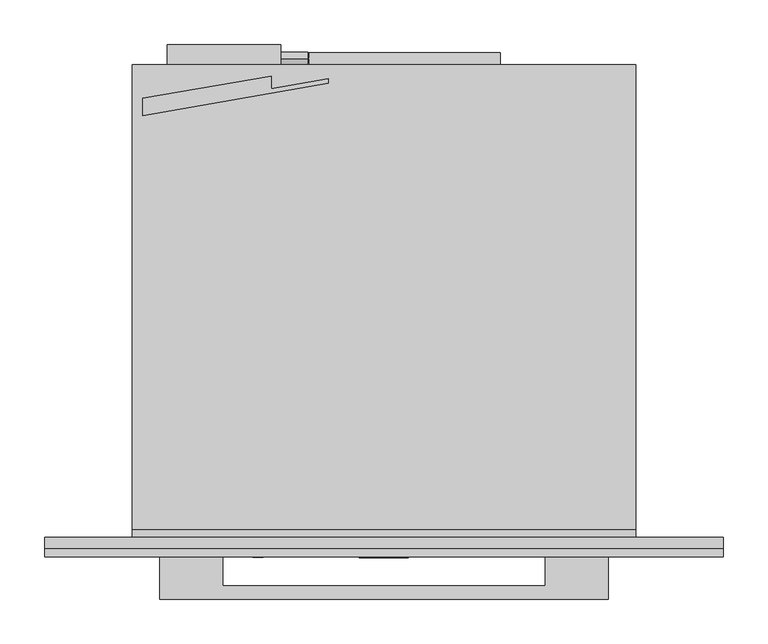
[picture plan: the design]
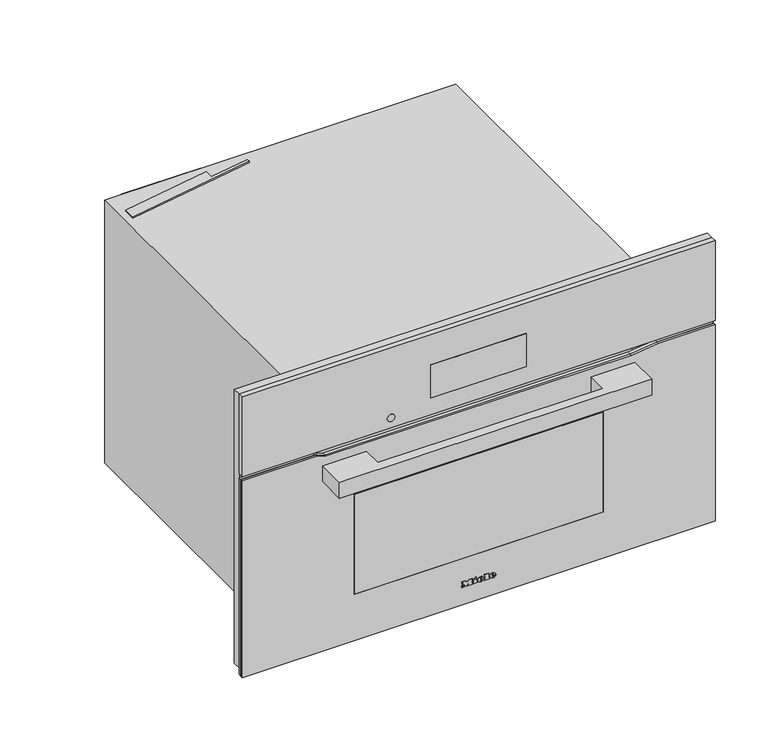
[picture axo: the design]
"""IFC4 building model written with IfcOpenShell, lengths in millimetres: proxy geometry."""

from ifc_helpers import new_model, si_unit, point, frame, frame_2d, origin, place, context, project, spatial, polyline, circle_curve, ellipse_curve, trimmed, segment, composite_curve, outline, extrude, faceted_brep, source, transform, mapped, element, save
from ifc_brep_helpers import plane_surface, cylinder_surface, revolved_surface, extruded_surface, advanced_brep


def specialty_equipment_e0231a5e(model_context):
    return source(origin(), model_context, "Body", "SolidModel", [
        advanced_brep(
        [(21.28, -23.0, 36.133), (21.28, -23.0, 37.042), (27.301, -23.0, 37.042), (16.825, -23.0, 37.042), (19.3, -23.0, 34.0), (27.148, -23.0, 36.133), (24.43, -23.0, 36.133), (22.288, -23.0, 35.125), (21.28, -23.0, 38.194), (21.28, -23.0, 39.175), (22.819, -23.0, 39.175), (22.819, -23.0, 38.194), (21.28, -22.0, 36.133), (22.288, -22.0, 35.125), (24.43, -22.0, 36.133), (27.148, -22.0, 36.133), (19.3, -22.0, 34.0), (16.825, -22.0, 37.042), (27.301, -22.0, 37.042), (21.28, -22.0, 37.042), (21.28, -22.0, 38.194), (22.819, -22.0, 38.194), (22.819, -22.0, 39.175), (21.28, -22.0, 39.175)],
        [
            (0, 1),
            (1, 2),
            (2, 3, ellipse_curve(frame((22.063, -23.0, 37.042), z_axis=(0.0, -1.0, 0.0), x_axis=(-1.0, 0.0, 0.0)), 5.238, 4.329)),
            (3, 4, circle_curve(frame((20.3080491, -23.0, 37.348), z_axis=(0.0, -1.0, 0.0), x_axis=(0.0, 0.0, -1.0)), 3.4964649)),
            (4, 5, circle_curve(frame((21.9581428, -23.0, 39.724), z_axis=(0.0, -1.0, 0.0), x_axis=(0.0, 0.0, -1.0)), 6.3110933)),
            (5, 6),
            (6, 7, circle_curve(frame((22.7279412, -23.0, 36.97), z_axis=(0.0, 1.0, 0.0), x_axis=(0.0, 0.0, -1.0)), 1.896727)),
            (7, 0, circle_curve(frame((22.288, -23.0, 36.133), z_axis=(0.0, 1.0, 0.0), x_axis=(0.0, 0.0, -1.0)), 1.008)),
            (8, 9),
            (9, 10, circle_curve(frame((22.0495, -23.0, 39.175), z_axis=(0.0, 1.0, 0.0), x_axis=(0.0, 0.0, -1.0)), 0.7695)),
            (10, 11),
            (11, 8),
            (12, 13, circle_curve(frame((22.288, -22.0, 36.133), z_axis=(0.0, -1.0, 0.0), x_axis=(0.0, 0.0, -1.0)), 1.008)),
            (13, 14, circle_curve(frame((22.7279412, -22.0, 36.97), z_axis=(0.0, -1.0, 0.0), x_axis=(0.0, 0.0, -1.0)), 1.896727)),
            (14, 15),
            (15, 16, circle_curve(frame((21.9581428, -22.0, 39.724), z_axis=(0.0, 1.0, 0.0), x_axis=(0.0, 0.0, -1.0)), 6.3110933)),
            (16, 17, circle_curve(frame((20.3080491, -22.0, 37.348), z_axis=(0.0, 1.0, 0.0), x_axis=(0.0, 0.0, -1.0)), 3.4964649)),
            (17, 18, ellipse_curve(frame((22.063, -22.0, 37.042), z_axis=(0.0, 1.0, 0.0), x_axis=(-1.0, 0.0, 0.0)), 5.238, 4.329)),
            (18, 19),
            (19, 12),
            (20, 21),
            (21, 22),
            (22, 23, circle_curve(frame((22.0495, -22.0, 39.175), z_axis=(0.0, -1.0, 0.0), x_axis=(0.0, 0.0, -1.0)), 0.7695)),
            (23, 20),
            (0, 12),
            (19, 1),
            (18, 2),
            (5, 15),
            (14, 6),
            (17, 3),
            (13, 7),
            (16, 4),
            (8, 20),
            (23, 9),
            (22, 10),
            (21, 11),
        ],
        [
            plane_surface(frame((21.28, -23.0, 37.042), z_axis=(0.0, -1.0, 0.0), x_axis=(0.0, 0.0, 1.0))),
            plane_surface(frame((21.28, -22.0, 37.042), z_axis=(0.0, 1.0, 0.0), x_axis=(0.0, 0.0, -1.0))),
            plane_surface(frame((21.28, -23.0, 36.133), z_axis=(1.0, 0.0, 0.0), x_axis=(0.0, 1.0, 0.0))),
            plane_surface(frame((21.28, -23.0, 37.042), z_axis=(0.0, 0.0, -1.0), x_axis=(0.0, 1.0, 0.0))),
            plane_surface(frame((27.148, -23.0, 36.133), z_axis=(0.0, 0.0, 1.0), x_axis=(0.0, 1.0, 0.0))),
            extruded_surface(trimmed(ellipse_curve(frame((22.063, -21.0, 37.042), z_axis=(0.0, -1.0, 0.0), x_axis=(-1.0, 0.0, 0.0)), 5.238, 4.329), [point((27.301, -21.0, 37.042))], [point((16.825, -21.0, 37.042))], True, "CARTESIAN"), (0.0, -1.0, 0.0), 1.0),
            revolved_surface(polyline([(22.7279412, -22.0, 35.073273), (22.7279412, -23.0, 35.073273)]), (22.7279412, -22.0, 36.97), (0.0, 1.0, 0.0)),
            revolved_surface(polyline([(22.288, -22.0, 35.125), (22.288, -23.0, 35.125)]), (22.288, -22.0, 36.133), (0.0, 1.0, 0.0)),
            cylinder_surface(frame((20.3080491, -22.0, 37.348), z_axis=(0.0, -1.0, 0.0), x_axis=(0.0, 0.0, -1.0)), 3.4964649),
            cylinder_surface(frame((21.9581428, -22.0, 39.724), z_axis=(0.0, -1.0, 0.0), x_axis=(0.0, 0.0, -1.0)), 6.3110933),
            plane_surface(frame((21.28, -23.0, 38.194), z_axis=(1.0, 0.0, 0.0), x_axis=(0.0, 1.0, 0.0))),
            revolved_surface(polyline([(22.0495, -22.0, 38.405499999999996), (22.0495, -23.0, 38.405499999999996)]), (22.0495, -22.0, 39.175), (0.0, 1.0, 0.0)),
            plane_surface(frame((22.819, -23.0, 39.175), z_axis=(-1.0, 0.0, 0.0), x_axis=(0.0, 1.0, 0.0))),
            plane_surface(frame((22.819, -23.0, 38.194), z_axis=(0.0, 0.0, 1.0), x_axis=(0.0, 1.0, 0.0))),
        ],
        [
            (0, [[1, 2, 3, 4, 5, 6, 7, 8], [9, 10, 11, 12]]),
            (1, [[13, 14, 15, 16, 17, 18, 19, 20], [21, 22, 23, 24]]),
            (2, [[-1, 25, -20, 26]]),
            (3, [[-2, -26, -19, 27]]),
            (4, [[-6, 28, -15, 29]]),
            (5, [[-3, -27, -18, 30]]),
            (6, [[-7, -29, -14, 31]]),
            (7, [[-8, -31, -13, -25]]),
            (8, [[-4, -30, -17, 32]]),
            (9, [[-5, -32, -16, -28]]),
            (10, [[-9, 33, -24, 34]]),
            (11, [[-10, -34, -23, 35]]),
            (12, [[-11, -35, -22, 36]]),
            (13, [[-12, -36, -21, -33]]),
        ],
    ),
        advanced_brep(
        [(2.497, -23.0, 36.133), (2.497, -23.0, 37.042), (8.518, -23.0, 37.042), (-1.958, -23.0, 37.042), (0.517, -23.0, 34.0), (8.365, -23.0, 36.133), (5.647, -23.0, 36.133), (3.505, -23.0, 35.125), (2.497, -23.0, 38.194), (2.497, -23.0, 39.175), (4.036, -23.0, 39.175), (4.036, -23.0, 38.194), (2.497, -22.0, 36.133), (3.505, -22.0, 35.125), (5.647, -22.0, 36.133), (8.365, -22.0, 36.133), (0.517, -22.0, 34.0), (-1.958, -22.0, 37.042), (8.518, -22.0, 37.042), (2.497, -22.0, 37.042), (2.497, -22.0, 38.194), (4.036, -22.0, 38.194), (4.036, -22.0, 39.175), (2.497, -22.0, 39.175)],
        [
            (0, 1),
            (1, 2),
            (2, 3, ellipse_curve(frame((3.28, -23.0, 37.042), z_axis=(0.0, -1.0, 0.0), x_axis=(-1.0, 0.0, 0.0)), 5.238, 4.329)),
            (3, 4, circle_curve(frame((1.5250491, -23.0, 37.348), z_axis=(0.0, -1.0, 0.0), x_axis=(0.0, 0.0, -1.0)), 3.4964649)),
            (4, 5, circle_curve(frame((3.1751428, -23.0, 39.724), z_axis=(0.0, -1.0, 0.0), x_axis=(0.0, 0.0, -1.0)), 6.3110933)),
            (5, 6),
            (6, 7, circle_curve(frame((3.9449412, -23.0, 36.97), z_axis=(0.0, 1.0, 0.0), x_axis=(0.0, 0.0, -1.0)), 1.896727)),
            (7, 0, circle_curve(frame((3.505, -23.0, 36.133), z_axis=(0.0, 1.0, 0.0), x_axis=(0.0, 0.0, -1.0)), 1.008)),
            (8, 9),
            (9, 10, circle_curve(frame((3.2665, -23.0, 39.175), z_axis=(0.0, 1.0, 0.0), x_axis=(0.0, 0.0, -1.0)), 0.7695)),
            (10, 11),
            (11, 8),
            (12, 13, circle_curve(frame((3.505, -22.0, 36.133), z_axis=(0.0, -1.0, 0.0), x_axis=(0.0, 0.0, -1.0)), 1.008)),
            (13, 14, circle_curve(frame((3.9449412, -22.0, 36.97), z_axis=(0.0, -1.0, 0.0), x_axis=(0.0, 0.0, -1.0)), 1.896727)),
            (14, 15),
            (15, 16, circle_curve(frame((3.1751428, -22.0, 39.724), z_axis=(0.0, 1.0, 0.0), x_axis=(0.0, 0.0, -1.0)), 6.3110933)),
            (16, 17, circle_curve(frame((1.5250491, -22.0, 37.348), z_axis=(0.0, 1.0, 0.0), x_axis=(0.0, 0.0, -1.0)), 3.4964649)),
            (17, 18, ellipse_curve(frame((3.28, -22.0, 37.042), z_axis=(0.0, 1.0, 0.0), x_axis=(-1.0, 0.0, 0.0)), 5.238, 4.329)),
            (18, 19),
            (19, 12),
            (20, 21),
            (21, 22),
            (22, 23, circle_curve(frame((3.2665, -22.0, 39.175), z_axis=(0.0, -1.0, 0.0), x_axis=(0.0, 0.0, -1.0)), 0.7695)),
            (23, 20),
            (0, 12),
            (19, 1),
            (18, 2),
            (5, 15),
            (14, 6),
            (17, 3),
            (13, 7),
            (16, 4),
            (8, 20),
            (23, 9),
            (22, 10),
            (21, 11),
        ],
        [
            plane_surface(frame((2.497, -23.0, 37.042), z_axis=(0.0, -1.0, 0.0), x_axis=(0.0, 0.0, 1.0))),
            plane_surface(frame((2.497, -22.0, 37.042), z_axis=(0.0, 1.0, 0.0), x_axis=(0.0, 0.0, -1.0))),
            plane_surface(frame((2.497, -23.0, 36.133), z_axis=(1.0, 0.0, 0.0), x_axis=(0.0, 1.0, 0.0))),
            plane_surface(frame((2.497, -23.0, 37.042), z_axis=(0.0, 0.0, -1.0), x_axis=(0.0, 1.0, 0.0))),
            plane_surface(frame((8.365, -23.0, 36.133), z_axis=(0.0, 0.0, 1.0), x_axis=(0.0, 1.0, 0.0))),
            extruded_surface(trimmed(ellipse_curve(frame((3.28, -21.0, 37.042), z_axis=(0.0, -1.0, 0.0), x_axis=(-1.0, 0.0, 0.0)), 5.238, 4.329), [point((8.518, -21.0, 37.042))], [point((-1.958, -21.0, 37.042))], True, "CARTESIAN"), (0.0, -1.0, 0.0), 1.0),
            revolved_surface(polyline([(3.9449412, -22.0, 35.073273), (3.9449412, -23.0, 35.073273)]), (3.9449412, -22.0, 36.97), (0.0, 1.0, 0.0)),
            revolved_surface(polyline([(3.505, -22.0, 35.125), (3.505, -23.0, 35.125)]), (3.505, -22.0, 36.133), (0.0, 1.0, 0.0)),
            cylinder_surface(frame((1.5250491, -22.0, 37.348), z_axis=(0.0, -1.0, 0.0), x_axis=(0.0, 0.0, -1.0)), 3.4964649),
            cylinder_surface(frame((3.1751428, -22.0, 39.724), z_axis=(0.0, -1.0, 0.0), x_axis=(0.0, 0.0, -1.0)), 6.3110933),
            plane_surface(frame((2.497, -23.0, 38.194), z_axis=(1.0, 0.0, 0.0), x_axis=(0.0, 1.0, 0.0))),
            revolved_surface(polyline([(3.2665, -22.0, 38.405499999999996), (3.2665, -23.0, 38.405499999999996)]), (3.2665, -22.0, 39.175), (0.0, 1.0, 0.0)),
            plane_surface(frame((4.036, -23.0, 39.175), z_axis=(-1.0, 0.0, 0.0), x_axis=(0.0, 1.0, 0.0))),
            plane_surface(frame((4.036, -23.0, 38.194), z_axis=(0.0, 0.0, 1.0), x_axis=(0.0, 1.0, 0.0))),
        ],
        [
            (0, [[1, 2, 3, 4, 5, 6, 7, 8], [9, 10, 11, 12]]),
            (1, [[13, 14, 15, 16, 17, 18, 19, 20], [21, 22, 23, 24]]),
            (2, [[-1, 25, -20, 26]]),
            (3, [[-2, -26, -19, 27]]),
            (4, [[-6, 28, -15, 29]]),
            (5, [[-3, -27, -18, 30]]),
            (6, [[-7, -29, -14, 31]]),
            (7, [[-8, -31, -13, -25]]),
            (8, [[-4, -30, -17, 32]]),
            (9, [[-5, -32, -16, -28]]),
            (10, [[-9, 33, -24, 34]]),
            (11, [[-10, -34, -23, 35]]),
            (12, [[-11, -35, -22, 36]]),
            (13, [[-12, -36, -21, -33]]),
        ],
    ),
        extrude(outline(polyline([(42.469, -7.34), (41.011, -6.656), (42.433, -3.605), (43.891, -4.28), (42.469, -7.34)])), frame((0.0, -23.0, 0.0), z_axis=(0.0, 1.0, 0.0), x_axis=(0.0, 0.0, 1.0)), (0.0, 0.0, 1.0), 1.0),
        extrude(outline(polyline([(40.813, -9.563), (39.202, -9.563), (39.202, -8.492), (35.512, -8.492), (35.512, -9.563), (34.0, -9.563), (34.0, -2.462), (35.512, -2.462), (35.512, -3.506), (40.813, -3.506), (40.813, -9.563)])), frame((0.0, -23.0, 0.0), z_axis=(0.0, 1.0, 0.0), x_axis=(0.0, 0.0, 1.0)), (0.0, 0.0, 1.0), 1.0),
        extrude(outline(polyline([(41.533, 9.022), (41.533, 10.102), (35.512, 10.102), (35.512, 9.022), (34.0, 9.022), (34.0, 16.321), (35.512, 16.321), (35.512, 15.214), (43.0, 15.214), (43.0, 9.022), (41.533, 9.022)])), frame((0.0, -23.0, 0.0), z_axis=(0.0, 1.0, 0.0), x_axis=(0.0, 0.0, 1.0)), (0.0, 0.0, 1.0), 1.0),
        extrude(outline(polyline([(41.533, -27.5), (41.533, -26.411), (35.512, -26.411), (35.512, -27.5), (34.0, -27.5), (34.0, -23.54), (35.512, -23.54), (35.512, -24.62), (39.3341247, -24.62), (34.0, -20.597), (39.4402223, -16.556), (35.512, -16.556), (35.512, -17.663), (34.0, -17.663), (34.0, -10.481), (35.512, -10.481), (35.512, -11.624), (41.533, -11.624), (41.533, -10.481), (43.0, -10.481), (43.0, -15.962), (39.625, -18.59), (43.0, -21.227), (43.0, -27.5), (41.533, -27.5)])), frame((0.0, -23.0, 0.0), z_axis=(0.0, 1.0, 0.0), x_axis=(0.0, 0.0, 1.0)), (0.0, 0.0, 1.0), 1.0),
        extrude(outline(polyline([(-250.0, -69.0), (-250.0, -22.0), (-180.0, -22.0), (-180.0, -54.0), (180.0, -54.0), (180.0, -22.0), (250.0, -22.0), (250.0, -69.0), (-250.0, -69.0)])), frame((0.0, 0.0, 291.0), z_axis=(0.0, 0.0, 1.0), x_axis=(1.0, 0.0, 0.0)), (0.0, 0.0, 1.0), 27.0),
        extrude(outline(polyline([(337.0, -378.5), (4.0, -378.5), (4.0, 378.5), (337.0, 378.5), (337.0, 287.3542631), (332.0, 244.0), (332.0, -244.0), (337.0, -260.3542631), (337.0, -378.5)])), frame((0.0, -18.0, 0.0), z_axis=(0.0, 1.0, 0.0), x_axis=(0.0, 0.0, 1.0)), (0.0, 0.0, 1.0), 5.0),
        extrude(outline(polyline([(337.0, -378.5), (4.0, -378.5), (4.0, 378.5), (337.0, 378.5), (337.0, 287.3542631), (332.0, 244.0), (332.0, -244.0), (337.0, -260.3542631), (337.0, -378.5)]), holes=[polyline([(252.0, 199.5), (82.0, 199.5), (82.0, -199.5), (252.0, -199.5), (252.0, 199.5)])]), frame((0.0, -22.0, 0.0), z_axis=(0.0, 1.0, 0.0), x_axis=(0.0, 0.0, 1.0)), (0.0, 0.0, 1.0), 4.0),
        extrude(outline(polyline([(-199.5, -18.0), (199.5, -18.0), (199.5, -22.0), (-199.5, -22.0), (-199.5, -18.0)])), frame((0.0, 0.0, 82.0), z_axis=(0.0, 0.0, 1.0), x_axis=(1.0, 0.0, 0.0)), (0.0, 0.0, 1.0), 170.0),
        extrude(outline(polyline([(-76.5, -21.0), (76.5, -21.0), (76.5, -22.0), (-76.5, -22.0), (-76.5, -21.0)])), frame((0.0, 0.0, 372.0), z_axis=(0.0, 0.0, 1.0), x_axis=(1.0, 0.0, 0.0)), (0.0, 0.0, 1.0), 56.0),
        faceted_brep([(378.5, -13.0, 479.0), (378.5, -13.0, 344.0), (-378.5, -13.0, 344.0), (-378.5, -13.0, 479.0), (378.5, -22.0, 344.0), (-378.5, -22.0, 344.0), (378.5, -22.0, 479.0), (-378.5, -22.0, 479.0), (76.5, -22.0, 428.0), (76.5, -22.0, 372.0), (-76.5, -22.0, 372.0), (-76.5, -22.0, 428.0), (-76.5, -21.0, 372.0), (-76.5, -21.0, 428.0), (76.5, -21.0, 428.0), (76.5, -21.0, 372.0)], [[[0, 1, 2, 3]], [[4, 5, 2, 1]], [[6, 7, 5, 4], [8, 9, 10, 11]], [[12, 13, 11, 10]], [[13, 14, 8, 11]], [[7, 6, 0, 3]], [[5, 7, 3, 2]], [[6, 4, 1, 0]], [[14, 13, 12, 15]], [[14, 15, 9, 8]], [[15, 12, 10, 9]]]),
        extrude(outline(composite_curve([segment(trimmed(circle_curve(frame_2d((361.0, -140.5745637)), 6.0), [point((361.0, -146.5745637))], [point((361.0, -134.5745637))], False, "CARTESIAN"), True, "CONTINUOUS"), segment(trimmed(circle_curve(frame_2d((361.0, -140.5745637)), 6.0), [point((361.0, -134.5745637))], [point((361.0, -146.5745637))], False, "CARTESIAN"), True, "CONTINUOUS")], self_intersect=False)), frame((0.0, -22.5, 0.0), z_axis=(0.0, 1.0, 0.0), x_axis=(0.0, 0.0, 1.0)), (0.0, 0.0, 1.0), 1.0),
        extrude(outline(polyline([(-269.0, 490.2851942), (-126.0, 515.1547594), (-126.0, 500.9446163), (-62.0, 512.0750511), (-62.0, 507.0), (-269.0, 471.0), (-269.0, 490.2851942)])), frame((0.0, 0.0, 445.0), z_axis=(0.0, 0.0, 1.0), x_axis=(1.0, 0.0, 0.0)), (0.0, 0.0, 1.0), 2.0),
        extrude(outline(polyline([(528.134837, 358.3256163), (533.9911721, 358.3256163), (533.9911721, 357.3256163), (529.134837, 357.3256163), (529.134837, 353.8256163), (532.0849866, 353.8256163), (532.0849866, 352.8256163), (529.134837, 352.8256163), (529.134837, 349.3256163), (533.9911721, 349.3256163), (533.9911721, 348.3256163), (528.134837, 348.3256163), (528.134837, 358.3256163)])), frame((-85.0, 0.0, 0.0), z_axis=(1.0, 0.0, 0.0), x_axis=(0.0, 1.0, 0.0)), (0.0, 0.0, 1.0), 1.0),
        extrude(outline(polyline([(535.4911721, 348.3256163), (535.4911721, 358.3256163), (536.5959622, 358.3256163), (536.5959622, 349.3256163), (540.4911721, 349.3256163), (540.4911721, 348.3256163), (535.4911721, 348.3256163)])), frame((-85.0, 0.0, 0.0), z_axis=(1.0, 0.0, 0.0), x_axis=(0.0, 1.0, 0.0)), (0.0, 0.0, 1.0), 1.0),
        extrude(outline(composite_curve([segment(trimmed(circle_curve(frame_2d((534.0, 353.0)), 7.5), [point((534.0, 345.5))], [point((534.0, 360.5))], False, "CARTESIAN"), True, "CONTINUOUS"), segment(trimmed(circle_curve(frame_2d((534.0, 353.0)), 7.5), [point((534.0, 360.5))], [point((534.0, 345.5))], False, "CARTESIAN"), True, "CONTINUOUS")], self_intersect=False)), frame((-115.0, 0.0, 0.0), z_axis=(1.0, 0.0, 0.0), x_axis=(0.0, 1.0, 0.0)), (0.0, 0.0, 1.0), 30.0),
        extrude(outline(polyline([(-115.0, 528.0), (-242.0, 528.0), (-242.0, 550.0), (-115.0, 550.0), (-115.0, 528.0)])), frame((0.0, 0.0, 325.0), z_axis=(0.0, 0.0, 1.0), x_axis=(1.0, 0.0, 0.0)), (0.0, 0.0, 1.0), 103.0),
        faceted_brep([(272.5, 25.0, 344.0), (-272.5, 25.0, 344.0), (-272.5, 25.0, 15.0), (272.5, 25.0, 15.0), (-235.0, 25.0, 270.0), (235.0, 25.0, 270.0), (235.0, 25.0, 60.0), (-235.0, 25.0, 60.0), (272.5, 0.0, 344.0), (-272.5, 0.0, 344.0), (-272.5, 0.0, 15.0), (272.5, 0.0, 15.0), (281.0, 0.0, 0.0), (281.0, 528.0, 0.0), (281.0, 528.0, 445.0), (281.0, 9.0, 445.0), (281.0, 9.0, 440.0), (281.0, 0.0, 440.0), (-281.0, 9.0, 445.0), (-281.0, 528.0, 445.0), (-281.0, 528.0, 0.0), (-281.0, 0.0, 0.0), (-281.0, 0.0, 440.0), (-281.0, 9.0, 440.0), (235.0, 433.0, 270.0), (-235.0, 433.0, 270.0), (-235.0, 433.0, 60.0), (235.0, 433.0, 60.0)], [[[0, 1, 2, 3], [4, 5, 6, 7]], [[1, 0, 8, 9]], [[2, 1, 9, 10]], [[0, 3, 11, 8]], [[12, 13, 14, 15, 16, 17]], [[18, 19, 20, 21, 22, 23]], [[13, 12, 21, 20]], [[14, 13, 20, 19]], [[15, 14, 19, 18]], [[21, 12, 17, 22], [9, 8, 11, 10]], [[24, 25, 26, 27]], [[25, 24, 5, 4]], [[26, 25, 4, 7]], [[27, 26, 7, 6]], [[24, 27, 6, 5]], [[3, 2, 10, 11]], [[16, 23, 22, 17]], [[23, 16, 15, 18]]]),
        extrude(outline(polyline([(130.0, 528.0), (-130.0, 528.0), (-130.0, 541.0), (130.0, 541.0), (130.0, 528.0)])), frame((0.0, 0.0, 36.0), z_axis=(0.0, 0.0, 1.0), x_axis=(1.0, 0.0, 0.0)), (0.0, 0.0, 1.0), 260.0),
        extrude(outline(polyline([(15.0, 378.5), (479.0, 378.5), (479.0, -378.5), (15.0, -378.5), (15.0, -272.5), (344.0, -272.5), (344.0, 272.5), (15.0, 272.5), (15.0, 378.5)])), frame((0.0, -13.0, 0.0), z_axis=(0.0, 1.0, 0.0), x_axis=(0.0, 0.0, 1.0)), (0.0, 0.0, 1.0), 13.0),
    ])


if __name__ == "__main__":
    model = new_model("IFC4")
    model_context = context("Model", 3, world=origin())
    ifc_project = project(units=[si_unit("LENGTHUNIT", "METRE", prefix="MILLI")], contexts=[model_context])
    site = spatial("IfcSite", under=ifc_project)
    building = spatial("IfcBuilding", under=site)
    placement = place(None, origin())
    specialty_equipment_shape = specialty_equipment_e0231a5e(model_context)
    element("IfcBuildingElementProxy", 1, Name="Specialty Equipment", at=placement, inside=building, context=model_context, shape_type="MappedRepresentation", body=[
        mapped(specialty_equipment_shape, transform((0.0, 0.0, 0.0), x_axis=(1.0, 0.0, 0.0), y_axis=(0.0, 1.0, 0.0), z_axis=(0.0, 0.0, 1.0))),
    ])
    save(model, "model.ifc")
